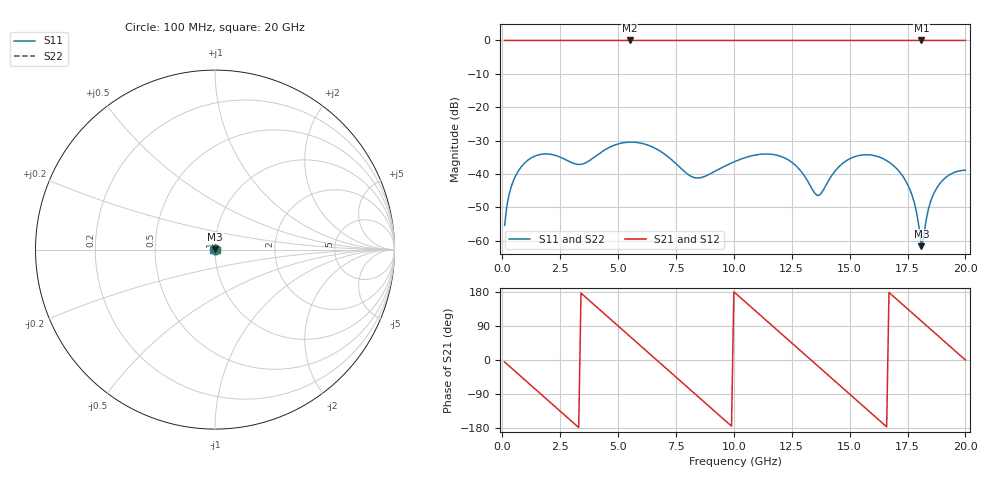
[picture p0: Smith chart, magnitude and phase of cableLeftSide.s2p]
! File created by SignalIntegrity v1.5.2: Signal and Power Integrity Tools
! https://github.com/Nubis-Communications/SignalIntegrity
# MHz S MA R 50.0
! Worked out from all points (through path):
!   200 points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, 100 MHz to 20 GHz, reference 50 ohm
!   highest |S21| = 0.00 dB at 18.1 GHz (marker M1); lowest = 0.0 dB at 5.5 GHz (marker M2)
!   group delay of S21, straight-line fit = 150 ps
!   lowest |S11| = -61.7 dB at 18.1 GHz (marker M3), VSWR 1.00, Z = 50 + j0.0672 ohm
!   |S11| at or under -10 dB: start of sweep to end of sweep
!   |S22| runs from -61.7 to -30.5 dB; largest |S21 - S12| = 0
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100  0.001692 85.1  1 -5.4  1 -5.4  0.001692 84.1
600  0.00972 60.7  1 -32.4  1 -32.4  0.00972 54.5
1700  0.01972 10.0  0.9998 -91.8  0.9998 -91.8  0.01972 -13.6
2700  0.01656 -21.1  0.9999 -145.8  0.9999 -145.8  0.01656 -90.5
3500  0.01419 -14.7  0.9999 171.0  0.9999 171.0  0.01419 176.7
4600  0.02473 -27.1  0.9997 111.6  0.9997 111.6  0.02473 70.3
5500  0.02993 -65.1  0.9996 63.0  0.9996 63.0  0.02993 11.1
6800  0.02214 -127.4  0.9998 -7.2  0.9998 -7.2  0.02214 -67.0
7700  0.01226 -160.7  0.9999 -55.8  0.9999 -55.8  0.01226 -130.8
8400  0.008673 -166.2  1 -93.6  1 -93.6  0.008673 159.0
9300  0.01151 166.7  0.9999 -142.2  0.9999 -142.2  0.01151 88.9
10100  0.01561 114.9  0.9999 174.6  0.9999 174.6  0.01561 54.3
11700  0.01954 7.7  0.9998 88.2  0.9998 88.2  0.01954 -11.3
12600  0.01405 -42.8  0.9999 39.6  0.9999 39.6  0.01405 -58.0
13400  0.005773 -56.4  1 -3.6  1 -3.6  0.005773 -130.8
15000  0.01682 -44.3  0.9999 -90.0  0.9999 -90.0  0.01682 44.3
16000  0.01899 -102.0  0.9998 -144.0  0.9998 -144.0  0.01899 -6.0
16700  0.01503 -145.9  0.9999 178.2  0.9999 178.2  0.01503 -37.7
17600  0.005871 151.8  1 129.6  1 129.6  0.005871 -72.6
18100  0.000826 54.4  1 102.6  1 102.6  0.000826 -29.2
18700  0.005625 -85.8  1 70.2  1 70.2  0.005625 46.2
20000  0.01134 -180.0  0.9999 0.0  0.9999 0.0  0.01134 0.0
